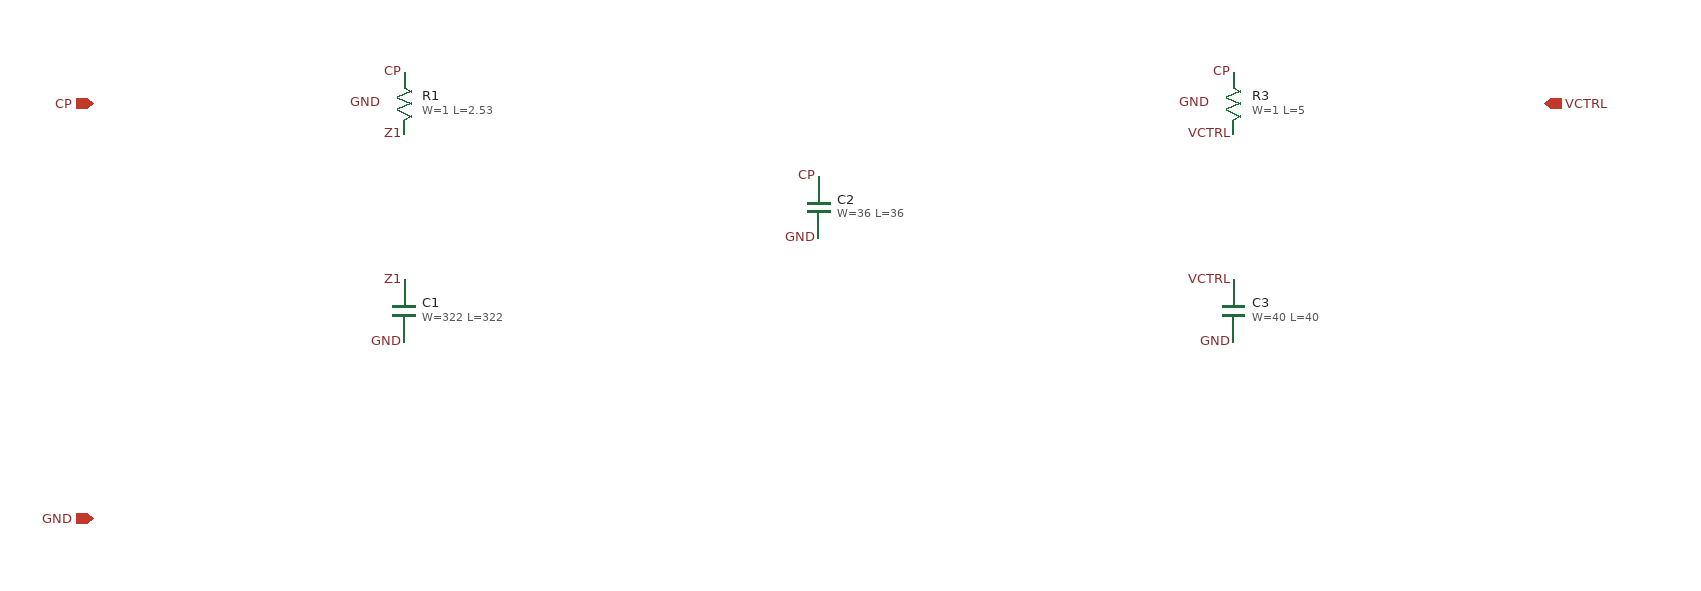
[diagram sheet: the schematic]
v {xschem version=3.4.7 file_version=1.2
* loop_filter_c2div4.sch -- a DELIBERATELY DEGRADED copy of the sky130 PLL loop filter.
* NOT part of the design: nothing under design/ instantiates it, and no spec
* row is claimed for it.
*
* Generated by sim/lf-c2-jitter-sensitivity/testbench/gen_c2_variant.py from
* design/loop-filter/loop_filter.sch. The body below is that file's own,
* verbatim, with exactly one substitution: C2's drawn geometry W=L=72 um ->
* W=L=36 um, i.e. C2's AREA divided by 4. R1, C1, R3 and C3 are
* untouched, and no other property of C2 changes.
*
* Why C2, and why an area divisor: C2 is the shunt capacitor at the charge-pump
* node whose stated design purpose (design/loop-filter/DESIGN.md, "Filter
* order" and "Topology") is to attenuate reference-frequency ripple reaching
* VCTRL. A narrow charge-pump correction pulse of current Icp and width dt
* develops roughly Icp*dt/C2 at that node, so shrinking C2 raises the ripple
* the VCO's control input sees roughly in proportion -- degrading exactly the
* mechanism ratified spec row 9 (period jitter) is measured over, and nothing
* else's design intent. It is also the loop-filter parameter least likely to
* stop the loop locking at all, which a negative control has to avoid (a draw
* that never locks carries no period-jitter figure to compare): per
* design/loop-filter/DESIGN.md's own derivation the C2 pole
* 1/(2*pi*R1*Ceff) moves further ABOVE the loop crossover as C2 shrinks, so
* the phase margin rows 6/7 are stated over does not degrade, and C2 is a few
* per cent of the C1+C2+C3 that same document identifies as the cold-start
* acquisition ramp's capacitance, so the ramp is essentially unchanged. Both
* statements are design-time reasoning about why this is the right knob; what
* the knob actually does to period jitter is what this unit MEASURES.
*
* Verification: `--check` mode of the generator re-derives this file from the
* committed design schematic and fails on any drift, so this copy cannot fall
* out of step with the design it degrades.
G {}
V {}
S {}
E {}
C {sky130_fd_pr/res_xhigh_po.sym} -400 -100 0 0 {name=R1
W=1
L=2.53
mult=1
model=res_xhigh_po
spiceprefix=X}
C {devices/lab_pin.sym} -400 -70 0 0 {name=p1 sig_type=std_logic lab=Z1}
C {devices/lab_pin.sym} -400 -130 0 0 {name=p2 sig_type=std_logic lab=CP}
C {devices/lab_pin.sym} -420 -100 0 0 {name=p3 sig_type=std_logic lab=GND}
C {sky130_fd_pr/cap_mim_m3_1.sym} -400 100 0 0 {name=C1
model=cap_mim_m3_1
W=322
L=322
MF=1
spiceprefix=X}
C {devices/lab_pin.sym} -400 70 0 0 {name=p4 sig_type=std_logic lab=Z1}
C {devices/lab_pin.sym} -400 130 0 0 {name=p5 sig_type=std_logic lab=GND}
C {sky130_fd_pr/cap_mim_m3_1.sym} 0 0 0 0 {name=C2
model=cap_mim_m3_1
W=36
L=36
MF=1
spiceprefix=X}
C {devices/lab_pin.sym} 0 -30 0 0 {name=p6 sig_type=std_logic lab=CP}
C {devices/lab_pin.sym} 0 30 0 0 {name=p7 sig_type=std_logic lab=GND}
C {sky130_fd_pr/res_xhigh_po.sym} 400 -100 0 0 {name=R3
W=1
L=5
mult=1
model=res_xhigh_po
spiceprefix=X}
C {devices/lab_pin.sym} 400 -70 0 0 {name=p8 sig_type=std_logic lab=VCTRL}
C {devices/lab_pin.sym} 400 -130 0 0 {name=p9 sig_type=std_logic lab=CP}
C {devices/lab_pin.sym} 380 -100 0 0 {name=p10 sig_type=std_logic lab=GND}
C {sky130_fd_pr/cap_mim_m3_1.sym} 400 100 0 0 {name=C3
model=cap_mim_m3_1
W=40
L=40
MF=1
spiceprefix=X}
C {devices/lab_pin.sym} 400 70 0 0 {name=p11 sig_type=std_logic lab=VCTRL}
C {devices/lab_pin.sym} 400 130 0 0 {name=p12 sig_type=std_logic lab=GND}
C {devices/ipin.sym} -700 -100 0 0 {name=p13 lab=CP}
C {devices/iopin.sym} -700 300 0 0 {name=p14 lab=GND}
C {devices/opin.sym} 700 -100 0 0 {name=p15 lab=VCTRL}
C {devices/title.sym} -400 -900 0 0 {name=l1 author="2AM Logic (issue #26, sky130 PLL loop filter)"}
